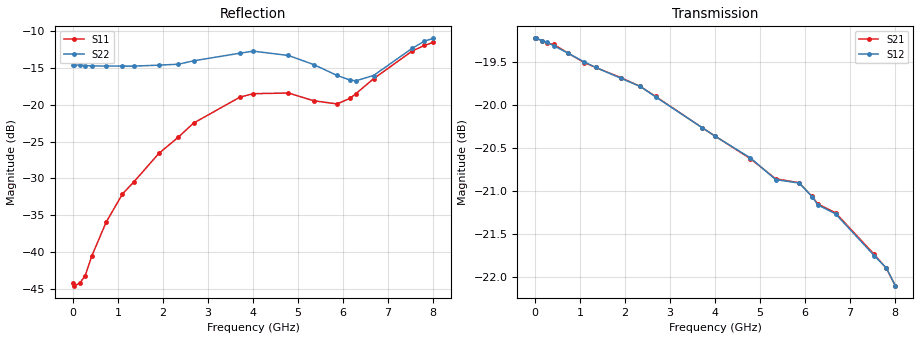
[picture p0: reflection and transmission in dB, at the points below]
! DEVICE ID: PE43712
! File Path: z:\PE43713\PE43713_CHAR_NOM_04292014\AMB\3p300\LS_ATT_18p00dB\PE43713_AMB_3p300V_3p000V_0p000V_LS_ATT_18p00dB_S2P_SN_10_A0139A.s2p
! Serial: 10
! Lot: A0139A
! Temp: 25C
! VDD: 3.300
! VSS: 0.000
! Control_Hi: 3.000
! Control_Lo: 0.000
! Attenuation Step: 18.00dB
! Port 1: RF1
! Port 2: RF2
! ThroughPath:1-2
! IDD: 0.0001464885
! ISS: -1.096e-007
#  Hz  S  RI  R  50
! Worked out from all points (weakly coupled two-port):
!   801 points, 10 MHz to 8.01 GHz, reference 50 ohm
!   highest |S21| = -19.22 dB at 10 MHz (marker M1); lowest = -22.1 dB at 8.01 GHz (marker M2)
!   lowest |S11| = -44.6 dB at 30 MHz (marker M3), VSWR 1.01, Z = 49.4 + j0.137 ohm
!   |S11| at or under -10 dB: start of sweep to end of sweep
!   |S22| runs from -16.7 to -10.9 dB; largest |S21 - S12| = 0.00041
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1e7  -0.00609 0.00056  0.1094 -0.000572  0.1094 -0.000527  -0.1879 0.00128
3e7  -0.00573 0.00139  0.1094 -0.00139  0.1094 -0.0014  -0.1873 0.00311
1.5e8  -0.00488 0.00371  0.1089 -0.00649  0.1089 -0.00649  -0.1858 0.0118
2.7e8  -0.0042 0.00544  0.1081 -0.0114  0.1082 -0.0115  -0.1841 0.0189
4.2e8  -0.00386 0.0086  0.1071 -0.0175  0.1069 -0.0175  -0.1821 0.0281
7.4e8  -0.00358 0.0156  0.1031 -0.0295  0.1031 -0.0295  -0.1769 0.0496
1.1e9  -0.00222 0.0247  0.0973 -0.0418  0.0974 -0.0418  -0.1688 0.0725
1.35e9  0.000165 0.0299  0.0928 -0.0496  0.0928 -0.0496  -0.162 0.0865
1.91e9  0.00878 0.046  0.0805 -0.0655  0.0804 -0.0655  -0.1408 0.1222
2.34e9  0.018 0.0576  0.069 -0.0759  0.069 -0.0759  -0.1208 0.1456
2.68e9  0.0268 0.0703  0.0592 -0.0821  0.0591 -0.0821  -0.1033 0.1707
3.71e9  0.0389 0.106  0.0261 -0.0935  0.0261 -0.0935  -0.0684 0.2142
4.01e9  0.04 0.1124  0.0166 -0.0945  0.0165 -0.0945  -0.0643 0.223
4.79e9  0.0436 0.1123  -0.00735 -0.0928  -0.00737 -0.0929  -0.0426 0.2127
5.35e9  0.056 0.0909  -0.0228 -0.0877  -0.0228 -0.0876  -0.0211 0.187
5.87e9  0.0767 0.0666  -0.037 -0.0822  -0.0369 -0.0822  0.0218 0.1571
6.16e9  0.0944 0.0585  -0.045 -0.0762  -0.0448 -0.0763  0.0533 0.1376
6.29e9  0.1057 0.0556  -0.0472 -0.0738  -0.047 -0.0738  0.0697 0.1283
6.68e9  0.1413 0.0521  -0.0552 -0.0667  -0.055 -0.0667  0.1181 0.1057
7.54e9  0.2242 0.0619  -0.0688 -0.0444  -0.0687 -0.0443  0.2208 0.1008
7.81e9  0.2441 0.0699  -0.0708 -0.038  -0.0708 -0.0381  0.2498 0.1063
8.01e9  0.2553 0.0763  -0.0712 -0.0331  -0.0711 -0.0333  0.2629 0.1064
